VERSION 5.8 ;
BUSBITCHARS "[]" ;
DIVIDERCHAR "/" ;
CLEARANCEMEASURE EUCLIDEAN ;

SITE coresite
    SIZE 0.0450 BY 0.1440 ;
    CLASS CORE ;
    SYMMETRY X Y ;
END coresite

SITE coresite_DH_N
    SIZE 0.0450 BY 0.2880 ;
    CLASS CORE ;
    SYMMETRY X Y ;
END coresite_DH_N

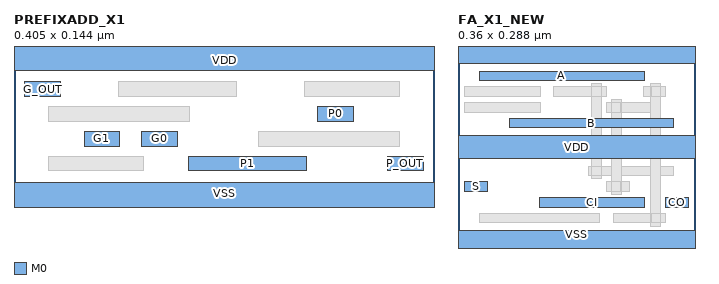
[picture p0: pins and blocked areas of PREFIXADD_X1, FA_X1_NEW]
MACRO PREFIXADD_X1
  CLASS CORE ;
  ORIGIN 0 0 ;
  FOREIGN PREFIXADD_X1 0 0 ;
  SIZE 0.405000 BY 0.144000 ;
  SYMMETRY X Y ;
  SITE coresite ;
  PIN G1
    DIRECTION INPUT ;
    USE SIGNAL ;
    PORT
      LAYER M0 ;
        RECT 0.067500 0.053000 0.102000 0.067000 ;
    END
  END G1
  PIN P1
    DIRECTION INPUT ;
    USE SIGNAL ;
    PORT
      LAYER M0 ;
        RECT 0.168000 0.029000 0.282000 0.043000 ;
    END
  END P1
  PIN G0
    DIRECTION INPUT ;
    USE SIGNAL ;
    PORT
      LAYER M0 ;
        RECT 0.123000 0.053000 0.157500 0.067000 ;
    END
  END G0
  PIN P0
    DIRECTION INPUT ;
    USE SIGNAL ;
    PORT
      LAYER M0 ;
        RECT 0.292500 0.077000 0.327000 0.091000 ;
    END
  END P0
  PIN VDD
    DIRECTION INOUT ;
    USE POWER ;
    SHAPE ABUTMENT ;
    PORT
      LAYER M0 ;
        RECT 0.000000 0.126000 0.405000 0.162000 ;
    END
  END VDD
  PIN VSS
    DIRECTION INOUT ;
    USE GROUND ;
    SHAPE ABUTMENT ;
    PORT
      LAYER M0 ;
        RECT 0.000000 -0.018000 0.405000 0.018000 ;
    END
  END VSS
  PIN G_OUT
    DIRECTION OUTPUT ;
    USE SIGNAL ;
    PORT
      LAYER M0 ;
        RECT 0.010500 0.101000 0.045000 0.115000 ;
    END
  END G_OUT
  PIN P_OUT
    DIRECTION OUTPUT ;
    USE SIGNAL ;
    PORT
      LAYER M0 ;
        RECT 0.360000 0.029000 0.394500 0.043000 ;
    END
  END P_OUT
  OBS
      LAYER M0 ;
        RECT 0.033000 0.029000 0.124500 0.043000 ;
        RECT 0.235500 0.053000 0.372000 0.067000 ;
        RECT 0.033000 0.077000 0.169500 0.091000 ;
        RECT 0.100500 0.101000 0.214500 0.115000 ;
        RECT 0.280500 0.101000 0.372000 0.115000 ;
  END
END PREFIXADD_X1

MACRO FA_X1_NEW
  CLASS CORE ;
  ORIGIN 0 0 ;
  FOREIGN FA_X1_NEW 0 0 ;
  SIZE 0.360000 BY 0.288000 ;
  SYMMETRY X Y ;
  SITE coresite_DH_N ;
  PIN A
    DIRECTION INPUT ;
    USE SIGNAL ;
    PORT
      LAYER M0 ;
        RECT 0.033000 0.245000 0.282000 0.259000 ;
    END
  END A
  PIN B
    DIRECTION INPUT ;
    USE SIGNAL ;
    PORT
      LAYER M0 ;
        RECT 0.078000 0.173000 0.327000 0.187000 ;
    END
  END B
  PIN CI
    DIRECTION INPUT ;
    USE SIGNAL ;
    PORT
      LAYER M0 ;
        RECT 0.123000 0.053000 0.282000 0.067000 ;
    END
  END CI
  PIN CO
    DIRECTION OUTPUT ;
    USE SIGNAL ;
    PORT
      LAYER M0 ;
        RECT 0.315000 0.053000 0.349500 0.067000 ;
    END
  END CO
  PIN S
    DIRECTION OUTPUT ;
    USE SIGNAL ;
    PORT
      LAYER M0 ;
        RECT 0.010500 0.077000 0.045000 0.091000 ;
    END
  END S
  PIN VDD
    DIRECTION INOUT ;
    USE POWER ;
    SHAPE ABUTMENT ;
    PORT
      LAYER M0 ;
        RECT 0.000000 0.126000 0.360000 0.162000 ;
    END
  END VDD
  PIN VSS
    DIRECTION INOUT ;
    USE GROUND ;
    SHAPE ABUTMENT ;
    PORT
      LAYER M0 ;
        RECT 0.000000 -0.018000 0.360000 0.018000 ;
        RECT 0.000000 0.270000 0.360000 0.306000 ;
    END
  END VSS
  OBS
      LAYER M0 ;
        RECT 0.033000 0.029000 0.214500 0.043000 ;
        RECT 0.235500 0.029000 0.315000 0.043000 ;
        RECT 0.225000 0.077000 0.259500 0.091000 ;
        RECT 0.198000 0.101000 0.327000 0.115000 ;
        RECT 0.010500 0.197000 0.124500 0.211000 ;
        RECT 0.225000 0.197000 0.304500 0.211000 ;
        RECT 0.010500 0.221000 0.124500 0.235000 ;
        RECT 0.145500 0.221000 0.225000 0.235000 ;
        RECT 0.280500 0.221000 0.315000 0.235000 ;
      LAYER M1 ;
        RECT 0.232500 0.072000 0.247500 0.216000 ;
        RECT 0.202500 0.096000 0.217500 0.240000 ;
        RECT 0.292500 0.024000 0.307500 0.240000 ;
      LAYER V0 ;
        RECT 0.293000 0.029000 0.307000 0.043000 ;
        RECT 0.233000 0.077000 0.247000 0.091000 ;
        RECT 0.203000 0.101000 0.217000 0.115000 ;
        RECT 0.233000 0.197000 0.247000 0.211000 ;
        RECT 0.203000 0.221000 0.217000 0.235000 ;
        RECT 0.293000 0.221000 0.307000 0.235000 ;
  END
END FA_X1_NEW

END LIBRARY
